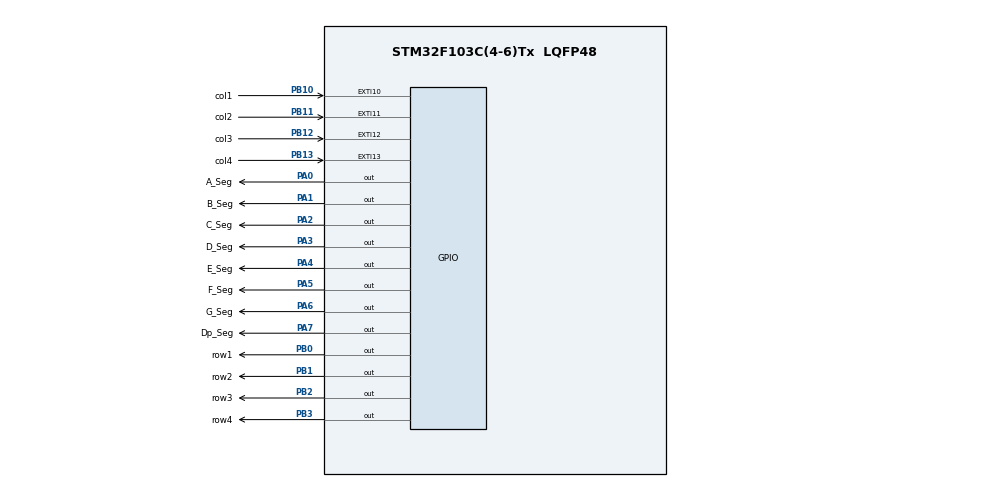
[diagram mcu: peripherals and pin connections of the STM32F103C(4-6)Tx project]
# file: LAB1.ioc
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Mcu.Family=STM32F1
Mcu.Name=STM32F103C(4-6)Tx
Mcu.Package=LQFP48
NVIC.EXTI15_10_IRQn=true\:0\:0\:false\:false\:true\:true\:true
NVIC.PriorityGroup=NVIC_PRIORITYGROUP_4
PA0-WKUP.GPIO_Label=A_Seg
PA0-WKUP.Signal=GPIO_Output
PA1.GPIO_Label=B_Seg
PA1.Signal=GPIO_Output
PA2.GPIO_Label=C_Seg
PA2.Signal=GPIO_Output
PA3.GPIO_Label=D_Seg
PA3.Signal=GPIO_Output
PA4.GPIO_Label=E_Seg
PA4.Signal=GPIO_Output
PA5.GPIO_Label=F_Seg
PA5.Signal=GPIO_Output
PA6.GPIO_Label=G_Seg
PA6.Signal=GPIO_Output
PA7.GPIO_Label=Dp_Seg
PA7.Signal=GPIO_Output
PB0.GPIO_Label=row1
PB0.Signal=GPIO_Output
PB1.GPIO_Label=row2
PB1.Signal=GPIO_Output
PB10.GPIO_Label=col1
PB10.GPIO_ModeDefaultEXTI=GPIO_MODE_IT_FALLING
PB10.GPIO_PuPd=GPIO_PULLUP
PB10.Signal=GPXTI10
PB11.GPIO_Label=col2
PB11.GPIO_ModeDefaultEXTI=GPIO_MODE_IT_FALLING
PB11.GPIO_PuPd=GPIO_PULLUP
PB11.Signal=GPXTI11
PB12.GPIO_Label=col3
PB12.GPIO_ModeDefaultEXTI=GPIO_MODE_IT_FALLING
PB12.GPIO_PuPd=GPIO_PULLUP
PB12.Signal=GPXTI12
PB13.GPIO_Label=col4
PB13.GPIO_ModeDefaultEXTI=GPIO_MODE_IT_FALLING
PB13.GPIO_PuPd=GPIO_PULLUP
PB13.Signal=GPXTI13
PB2.GPIO_Label=row3
PB2.Signal=GPIO_Output
PB3.GPIO_Label=row4
PB3.Signal=GPIO_Output
PD0-OSC_IN.Mode=HSE-External-Oscillator
PD0-OSC_IN.Signal=RCC_OSC_IN
PD1-OSC_OUT.Mode=HSE-External-Oscillator
PD1-OSC_OUT.Signal=RCC_OSC_OUT
ProjectManager.HeapSize=0x200
ProjectManager.StackSize=0x400
ProjectManager.TargetToolchain=MDK-ARM V5.27
RCC.AHBCLKDivider=RCC_SYSCLK_DIV2
RCC.AHBFreq_Value=36000000
RCC.APB1CLKDivider=RCC_HCLK_DIV2
RCC.APB1Freq_Value=18000000
RCC.APB1TimFreq_Value=36000000
RCC.APB2Freq_Value=36000000
RCC.APB2TimFreq_Value=36000000
RCC.HCLKFreq_Value=36000000
RCC.PLLMUL=RCC_PLL_MUL9
RCC.PLLSourceVirtual=RCC_PLLSOURCE_HSE
RCC.SYSCLKFreq_VALUE=72000000
RCC.SYSCLKSource=RCC_SYSCLKSOURCE_PLLCLK
RCC.USBFreq_Value=72000000
VP_SYS_VS_ND.Mode=No_Debug
board=custom

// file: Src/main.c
/* USER CODE BEGIN Header */
/**
  ******************************************************************************
  * @file           : main.c
  * @brief          : Main program body
  ******************************************************************************
  * @attention
  *
  * <h2><center>&copy; Copyright (c) 2020 STMicroelectronics.
  * All rights reserved.</center></h2>
  *
  * This software component is licensed by ST under BSD 3-Clause license,
  * the "License"; You may not use this file except in compliance with the
  * License. You may obtain a copy of the License at:
  *                        opensource.org/licenses/BSD-3-Clause
  *
  ******************************************************************************
  */
/* USER CODE END Header */

#include "main.h"
#include "gpio.h"

/* USER CODE BEGIN PD */
	//                     7     8      9    A     4      5    6  	 B      1    2     3     C     D     0     E    F
	uint8_t _7_seg[16] = {0x07, 0x7F, 0x6F, 0x77, 0x66, 0x6D, 0x7D, 0x7C, 0x06, 0x5B, 0x4F, 0x39, 0x5E, 0x3F, 0x79,0x71};
	void set_segment(uint8_t input);
	int flag_interupt=0; //when this flag set to high, one key is pressed and it's time to scan keypad.
	int keypad_scan();
	void shift(int i); //this function is used to move one zero between rows of keypad.

/* USER CODE END PD */

void SystemClock_Config(void);

int main(void)
{

  /* MCU Configuration--------------------------------------------------------*/

  /* Reset of all peripherals, Initializes the Flash interface and the Systick. */
  HAL_Init();

  /* Configure the system clock */
  SystemClock_Config();

  /* Initialize all configured peripherals */
  MX_GPIO_Init();

  /* Infinite loop */
  /* USER CODE BEGIN WHILE */
  while (1)
  {
		if(flag_interupt == 1) //if interupt has came.
		{
			set_segment(_7_seg[keypad_scan()]); //scan keyboard and change seven segment pins.
			flag_interupt = 0; //to get out of if.
		}

	}

    /* USER CODE END WHILE */

  }

void SystemClock_Config(void)
{
  RCC_OscInitTypeDef RCC_OscInitStruct = {0};
  RCC_ClkInitTypeDef RCC_ClkInitStruct = {0};

  /** Initializes the CPU, AHB and APB busses clocks
  */
  RCC_OscInitStruct.OscillatorType = RCC_OSCILLATORTYPE_HSE;
  RCC_OscInitStruct.HSEState = RCC_HSE_ON;
  RCC_OscInitStruct.HSEPredivValue = RCC_HSE_PREDIV_DIV1;
  RCC_OscInitStruct.HSIState = RCC_HSI_ON;
  RCC_OscInitStruct.PLL.PLLState = RCC_PLL_ON;
  RCC_OscInitStruct.PLL.PLLSource = RCC_PLLSOURCE_HSE;
  RCC_OscInitStruct.PLL.PLLMUL = RCC_PLL_MUL9;
  if (HAL_RCC_OscConfig(&RCC_OscInitStruct) != HAL_OK)
  {
    Error_Handler();
  }
  /** Initializes the CPU, AHB and APB busses clocks
  */
  RCC_ClkInitStruct.ClockType = RCC_CLOCKTYPE_HCLK|RCC_CLOCKTYPE_SYSCLK
                              |RCC_CLOCKTYPE_PCLK1|RCC_CLOCKTYPE_PCLK2;
  RCC_ClkInitStruct.SYSCLKSource = RCC_SYSCLKSOURCE_PLLCLK;
  RCC_ClkInitStruct.AHBCLKDivider = RCC_SYSCLK_DIV2;
  RCC_ClkInitStruct.APB1CLKDivider = RCC_HCLK_DIV2;
  RCC_ClkInitStruct.APB2CLKDivider = RCC_HCLK_DIV2;

  if (HAL_RCC_ClockConfig(&RCC_ClkInitStruct, FLASH_LATENCY_2) != HAL_OK)
  {
    Error_Handler();
  }
}

/* USER CODE BEGIN 4 */

void set_segment(uint8_t input)
{
	GPIOA -> ODR = input;  //with this register we can set value to pins of GPIOA.(output data register)
}

void HAL_GPIO_EXTI_Callback(uint16_t GPIO_Pin)
{
	flag_interupt = 1; // interupt has come.
}

void shift(int i)
{
	unsigned char pins[4] = {0x07,0xB,0xD,0xE};

	HAL_GPIO_WritePin(row1_GPIO_Port,row1_Pin,(GPIO_PinState) (pins[i] & 0x8)); //if output of (pins[i] & 0x8) is anything excpet 0x00 it will cast to GPIO_PIN_SET
	HAL_GPIO_WritePin(row2_GPIO_Port,row2_Pin,(GPIO_PinState) (pins[i] & 0x4));
	HAL_GPIO_WritePin(row3_GPIO_Port,row3_Pin,(GPIO_PinState) (pins[i] & 0x2));
	HAL_GPIO_WritePin(row4_GPIO_Port,row4_Pin,(GPIO_PinState) (pins[i] & 0x1));
}

int keypad_scan()
{
	int position; //position in keys array.

	for (int row = 0; row<4; row++)
	{
		shift(row); //shifting zero in rows.
		int col = -1;
		if(HAL_GPIO_ReadPin(col1_GPIO_Port,col1_Pin) == GPIO_PIN_RESET) //reading which column is pressed.
			col = 0;
		if(HAL_GPIO_ReadPin(col2_GPIO_Port,col2_Pin) == GPIO_PIN_RESET)
			col = 1;
		if(HAL_GPIO_ReadPin(col3_GPIO_Port,col3_Pin) == GPIO_PIN_RESET)
			col = 2;
		if(HAL_GPIO_ReadPin(col4_GPIO_Port,col4_Pin) == GPIO_PIN_RESET)
			col = 3;
		if(col != -1) //some key is pressed.
		{

			position = 4 * row + col; //finding index of pressed key in array with variables, row and col. (according to the _7_seg[16] array)
			col = -1;
			HAL_GPIO_WritePin(row1_GPIO_Port,row1_Pin,GPIO_PIN_RESET);
			HAL_GPIO_WritePin(row2_GPIO_Port,row2_Pin,GPIO_PIN_RESET); //reseting pins to initial values so when some key is pressed,we have falling edge interupt again.
			HAL_GPIO_WritePin(row3_GPIO_Port,row3_Pin,GPIO_PIN_RESET);
			HAL_GPIO_WritePin(row4_GPIO_Port,row4_Pin,GPIO_PIN_RESET);
			return position;
		}
	}
}

/* USER CODE END 4 */

void Error_Handler(void)
{
}

/************************ (C) COPYRIGHT STMicroelectronics *****END OF FILE****/
